VERSION 5.8 ;
BUSBITCHARS "[]" ;
DIVIDERCHAR "/" ;
UNITS
    DATABASE MICRONS 1000 ;
END UNITS

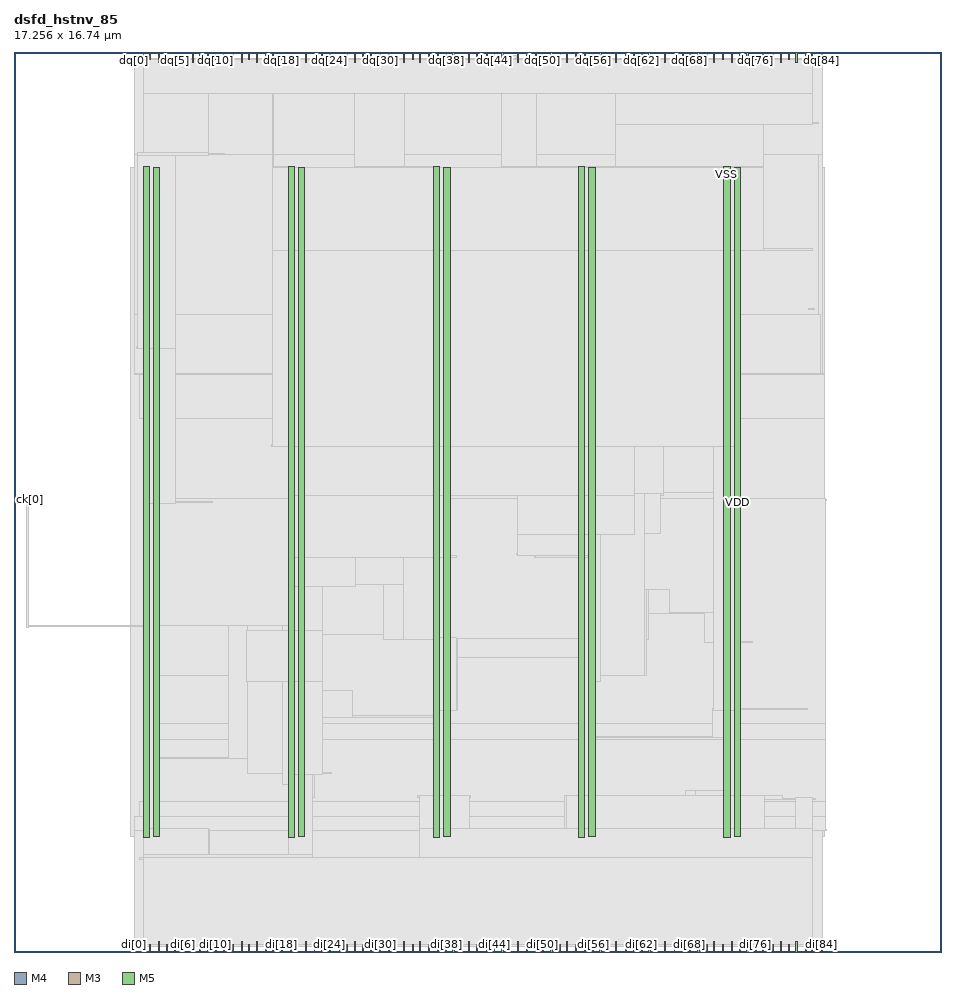
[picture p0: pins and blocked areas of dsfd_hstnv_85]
MACRO dsfd_hstnv_85
  FOREIGN dsfd_hstnv_85 0 0 ;
  CLASS BLOCK ;
  SIZE 17.256 BY 16.74 ;
  PIN ck[0]
    DIRECTION INPUT ;
    USE SIGNAL ;
    PORT
      LAYER M4 ;
        RECT  0 8.4 0.192 8.424 ;
    END
  END ck[0]
  PIN di[0]
    DIRECTION INPUT ;
    USE SIGNAL ;
    PORT
      LAYER M3 ;
        RECT  2.232 0 2.25 0.144 ;
    END
  END di[0]
  PIN di[10]
    DIRECTION INPUT ;
    USE SIGNAL ;
    PORT
      LAYER M3 ;
        RECT  3.744 0 3.762 0.144 ;
    END
  END di[10]
  PIN di[11]
    DIRECTION INPUT ;
    USE SIGNAL ;
    PORT
      LAYER M5 ;
        RECT  3.888 0 3.912 0.192 ;
    END
  END di[11]
  PIN di[12]
    DIRECTION INPUT ;
    USE SIGNAL ;
    PORT
      LAYER M3 ;
        RECT  4.068 0 4.086 0.144 ;
    END
  END di[12]
  PIN di[13]
    DIRECTION INPUT ;
    USE SIGNAL ;
    PORT
      LAYER M5 ;
        RECT  4.224 0 4.248 0.192 ;
    END
  END di[13]
  PIN di[14]
    DIRECTION INPUT ;
    USE SIGNAL ;
    PORT
      LAYER M3 ;
        RECT  4.356 0 4.374 0.144 ;
    END
  END di[14]
  PIN di[15]
    DIRECTION INPUT ;
    USE SIGNAL ;
    PORT
      LAYER M5 ;
        RECT  4.512 0 4.536 0.192 ;
    END
  END di[15]
  PIN di[16]
    DIRECTION INPUT ;
    USE SIGNAL ;
    PORT
      LAYER M3 ;
        RECT  4.68 0 4.698 0.144 ;
    END
  END di[16]
  PIN di[17]
    DIRECTION INPUT ;
    USE SIGNAL ;
    PORT
      LAYER M5 ;
        RECT  4.8 0 4.824 0.192 ;
    END
  END di[17]
  PIN di[18]
    DIRECTION INPUT ;
    USE SIGNAL ;
    PORT
      LAYER M3 ;
        RECT  4.968 0 4.986 0.144 ;
    END
  END di[18]
  PIN di[19]
    DIRECTION INPUT ;
    USE SIGNAL ;
    PORT
      LAYER M5 ;
        RECT  5.136 0 5.16 0.192 ;
    END
  END di[19]
  PIN di[1]
    DIRECTION INPUT ;
    USE SIGNAL ;
    PORT
      LAYER M5 ;
        RECT  2.4 0 2.424 0.192 ;
    END
  END di[1]
  PIN di[20]
    DIRECTION INPUT ;
    USE SIGNAL ;
    PORT
      LAYER M3 ;
        RECT  5.256 0 5.274 0.144 ;
    END
  END di[20]
  PIN di[21]
    DIRECTION INPUT ;
    USE SIGNAL ;
    PORT
      LAYER M5 ;
        RECT  5.424 0 5.448 0.192 ;
    END
  END di[21]
  PIN di[22]
    DIRECTION INPUT ;
    USE SIGNAL ;
    PORT
      LAYER M3 ;
        RECT  5.58 0 5.598 0.144 ;
    END
  END di[22]
  PIN di[23]
    DIRECTION INPUT ;
    USE SIGNAL ;
    PORT
      LAYER M5 ;
        RECT  5.712 0 5.736 0.192 ;
    END
  END di[23]
  PIN di[24]
    DIRECTION INPUT ;
    USE SIGNAL ;
    PORT
      LAYER M3 ;
        RECT  5.868 0 5.886 0.144 ;
    END
  END di[24]
  PIN di[25]
    DIRECTION INPUT ;
    USE SIGNAL ;
    PORT
      LAYER M5 ;
        RECT  6.048 0 6.072 0.192 ;
    END
  END di[25]
  PIN di[26]
    DIRECTION INPUT ;
    USE SIGNAL ;
    PORT
      LAYER M3 ;
        RECT  6.192 0 6.21 0.144 ;
    END
  END di[26]
  PIN di[27]
    DIRECTION INPUT ;
    USE SIGNAL ;
    PORT
      LAYER M5 ;
        RECT  6.336 0 6.36 0.192 ;
    END
  END di[27]
  PIN di[28]
    DIRECTION INPUT ;
    USE SIGNAL ;
    PORT
      LAYER M3 ;
        RECT  6.48 0 6.498 0.144 ;
    END
  END di[28]
  PIN di[29]
    DIRECTION INPUT ;
    USE SIGNAL ;
    PORT
      LAYER M5 ;
        RECT  6.624 0 6.648 0.192 ;
    END
  END di[29]
  PIN di[2]
    DIRECTION INPUT ;
    USE SIGNAL ;
    PORT
      LAYER M3 ;
        RECT  2.52 0 2.538 0.144 ;
    END
  END di[2]
  PIN di[30]
    DIRECTION INPUT ;
    USE SIGNAL ;
    PORT
      LAYER M3 ;
        RECT  6.804 0 6.822 0.144 ;
    END
  END di[30]
  PIN di[31]
    DIRECTION INPUT ;
    USE SIGNAL ;
    PORT
      LAYER M5 ;
        RECT  6.96 0 6.984 0.192 ;
    END
  END di[31]
  PIN di[32]
    DIRECTION INPUT ;
    USE SIGNAL ;
    PORT
      LAYER M3 ;
        RECT  7.092 0 7.11 0.144 ;
    END
  END di[32]
  PIN di[33]
    DIRECTION INPUT ;
    USE SIGNAL ;
    PORT
      LAYER M5 ;
        RECT  7.248 0 7.272 0.192 ;
    END
  END di[33]
  PIN di[34]
    DIRECTION INPUT ;
    USE SIGNAL ;
    PORT
      LAYER M3 ;
        RECT  7.416 0 7.434 0.144 ;
    END
  END di[34]
  PIN di[35]
    DIRECTION INPUT ;
    USE SIGNAL ;
    PORT
      LAYER M5 ;
        RECT  7.536 0 7.56 0.192 ;
    END
  END di[35]
  PIN di[36]
    DIRECTION INPUT ;
    USE SIGNAL ;
    PORT
      LAYER M3 ;
        RECT  7.704 0 7.722 0.144 ;
    END
  END di[36]
  PIN di[37]
    DIRECTION INPUT ;
    USE SIGNAL ;
    PORT
      LAYER M5 ;
        RECT  7.872 0 7.896 0.192 ;
    END
  END di[37]
  PIN di[38]
    DIRECTION INPUT ;
    USE SIGNAL ;
    PORT
      LAYER M3 ;
        RECT  8.028 0 8.046 0.144 ;
    END
  END di[38]
  PIN di[39]
    DIRECTION INPUT ;
    USE SIGNAL ;
    PORT
      LAYER M5 ;
        RECT  8.16 0 8.184 0.192 ;
    END
  END di[39]
  PIN di[3]
    DIRECTION INPUT ;
    USE SIGNAL ;
    PORT
      LAYER M5 ;
        RECT  2.688 0 2.712 0.192 ;
    END
  END di[3]
  PIN di[40]
    DIRECTION INPUT ;
    USE SIGNAL ;
    PORT
      LAYER M3 ;
        RECT  8.316 0 8.334 0.144 ;
    END
  END di[40]
  PIN di[41]
    DIRECTION INPUT ;
    USE SIGNAL ;
    PORT
      LAYER M5 ;
        RECT  8.448 0 8.472 0.192 ;
    END
  END di[41]
  PIN di[42]
    DIRECTION INPUT ;
    USE SIGNAL ;
    PORT
      LAYER M3 ;
        RECT  8.604 0 8.622 0.144 ;
    END
  END di[42]
  PIN di[43]
    DIRECTION INPUT ;
    USE SIGNAL ;
    PORT
      LAYER M5 ;
        RECT  8.784 0 8.808 0.192 ;
    END
  END di[43]
  PIN di[44]
    DIRECTION INPUT ;
    USE SIGNAL ;
    PORT
      LAYER M3 ;
        RECT  8.928 0 8.946 0.144 ;
    END
  END di[44]
  PIN di[45]
    DIRECTION INPUT ;
    USE SIGNAL ;
    PORT
      LAYER M5 ;
        RECT  9.072 0 9.096 0.192 ;
    END
  END di[45]
  PIN di[46]
    DIRECTION INPUT ;
    USE SIGNAL ;
    PORT
      LAYER M3 ;
        RECT  9.216 0 9.234 0.144 ;
    END
  END di[46]
  PIN di[47]
    DIRECTION INPUT ;
    USE SIGNAL ;
    PORT
      LAYER M5 ;
        RECT  9.36 0 9.384 0.192 ;
    END
  END di[47]
  PIN di[48]
    DIRECTION INPUT ;
    USE SIGNAL ;
    PORT
      LAYER M3 ;
        RECT  9.54 0 9.558 0.144 ;
    END
  END di[48]
  PIN di[49]
    DIRECTION INPUT ;
    USE SIGNAL ;
    PORT
      LAYER M5 ;
        RECT  9.696 0 9.72 0.192 ;
    END
  END di[49]
  PIN di[4]
    DIRECTION INPUT ;
    USE SIGNAL ;
    PORT
      LAYER M3 ;
        RECT  2.844 0 2.862 0.144 ;
    END
  END di[4]
  PIN di[50]
    DIRECTION INPUT ;
    USE SIGNAL ;
    PORT
      LAYER M3 ;
        RECT  9.828 0 9.846 0.144 ;
    END
  END di[50]
  PIN di[51]
    DIRECTION INPUT ;
    USE SIGNAL ;
    PORT
      LAYER M5 ;
        RECT  9.984 0 10.008 0.192 ;
    END
  END di[51]
  PIN di[52]
    DIRECTION INPUT ;
    USE SIGNAL ;
    PORT
      LAYER M3 ;
        RECT  10.152 0 10.17 0.144 ;
    END
  END di[52]
  PIN di[53]
    DIRECTION INPUT ;
    USE SIGNAL ;
    PORT
      LAYER M5 ;
        RECT  10.272 0 10.296 0.192 ;
    END
  END di[53]
  PIN di[54]
    DIRECTION INPUT ;
    USE SIGNAL ;
    PORT
      LAYER M3 ;
        RECT  10.44 0 10.458 0.144 ;
    END
  END di[54]
  PIN di[55]
    DIRECTION INPUT ;
    USE SIGNAL ;
    PORT
      LAYER M5 ;
        RECT  10.608 0 10.632 0.192 ;
    END
  END di[55]
  PIN di[56]
    DIRECTION INPUT ;
    USE SIGNAL ;
    PORT
      LAYER M3 ;
        RECT  10.764 0 10.782 0.144 ;
    END
  END di[56]
  PIN di[57]
    DIRECTION INPUT ;
    USE SIGNAL ;
    PORT
      LAYER M5 ;
        RECT  10.896 0 10.92 0.192 ;
    END
  END di[57]
  PIN di[58]
    DIRECTION INPUT ;
    USE SIGNAL ;
    PORT
      LAYER M3 ;
        RECT  11.052 0 11.07 0.144 ;
    END
  END di[58]
  PIN di[59]
    DIRECTION INPUT ;
    USE SIGNAL ;
    PORT
      LAYER M5 ;
        RECT  11.184 0 11.208 0.192 ;
    END
  END di[59]
  PIN di[5]
    DIRECTION INPUT ;
    USE SIGNAL ;
    PORT
      LAYER M5 ;
        RECT  2.976 0 3 0.192 ;
    END
  END di[5]
  PIN di[60]
    DIRECTION INPUT ;
    USE SIGNAL ;
    PORT
      LAYER M3 ;
        RECT  11.376 0 11.394 0.144 ;
    END
  END di[60]
  PIN di[61]
    DIRECTION INPUT ;
    USE SIGNAL ;
    PORT
      LAYER M5 ;
        RECT  11.52 0 11.544 0.192 ;
    END
  END di[61]
  PIN di[62]
    DIRECTION INPUT ;
    USE SIGNAL ;
    PORT
      LAYER M3 ;
        RECT  11.664 0 11.682 0.144 ;
    END
  END di[62]
  PIN di[63]
    DIRECTION INPUT ;
    USE SIGNAL ;
    PORT
      LAYER M5 ;
        RECT  11.808 0 11.832 0.192 ;
    END
  END di[63]
  PIN di[64]
    DIRECTION INPUT ;
    USE SIGNAL ;
    PORT
      LAYER M3 ;
        RECT  11.952 0 11.97 0.144 ;
    END
  END di[64]
  PIN di[65]
    DIRECTION INPUT ;
    USE SIGNAL ;
    PORT
      LAYER M5 ;
        RECT  12.096 0 12.12 0.192 ;
    END
  END di[65]
  PIN di[66]
    DIRECTION INPUT ;
    USE SIGNAL ;
    PORT
      LAYER M3 ;
        RECT  12.276 0 12.294 0.144 ;
    END
  END di[66]
  PIN di[67]
    DIRECTION INPUT ;
    USE SIGNAL ;
    PORT
      LAYER M5 ;
        RECT  12.432 0 12.456 0.192 ;
    END
  END di[67]
  PIN di[68]
    DIRECTION INPUT ;
    USE SIGNAL ;
    PORT
      LAYER M3 ;
        RECT  12.564 0 12.582 0.144 ;
    END
  END di[68]
  PIN di[69]
    DIRECTION INPUT ;
    USE SIGNAL ;
    PORT
      LAYER M5 ;
        RECT  12.72 0 12.744 0.192 ;
    END
  END di[69]
  PIN di[6]
    DIRECTION INPUT ;
    USE SIGNAL ;
    PORT
      LAYER M3 ;
        RECT  3.132 0 3.15 0.144 ;
    END
  END di[6]
  PIN di[70]
    DIRECTION INPUT ;
    USE SIGNAL ;
    PORT
      LAYER M3 ;
        RECT  12.888 0 12.906 0.144 ;
    END
  END di[70]
  PIN di[71]
    DIRECTION INPUT ;
    USE SIGNAL ;
    PORT
      LAYER M5 ;
        RECT  13.008 0 13.032 0.192 ;
    END
  END di[71]
  PIN di[72]
    DIRECTION INPUT ;
    USE SIGNAL ;
    PORT
      LAYER M3 ;
        RECT  13.176 0 13.194 0.144 ;
    END
  END di[72]
  PIN di[73]
    DIRECTION INPUT ;
    USE SIGNAL ;
    PORT
      LAYER M5 ;
        RECT  13.344 0 13.368 0.192 ;
    END
  END di[73]
  PIN di[74]
    DIRECTION INPUT ;
    USE SIGNAL ;
    PORT
      LAYER M3 ;
        RECT  13.5 0 13.518 0.144 ;
    END
  END di[74]
  PIN di[75]
    DIRECTION INPUT ;
    USE SIGNAL ;
    PORT
      LAYER M5 ;
        RECT  13.632 0 13.656 0.192 ;
    END
  END di[75]
  PIN di[76]
    DIRECTION INPUT ;
    USE SIGNAL ;
    PORT
      LAYER M3 ;
        RECT  13.788 0 13.806 0.144 ;
    END
  END di[76]
  PIN di[77]
    DIRECTION INPUT ;
    USE SIGNAL ;
    PORT
      LAYER M5 ;
        RECT  13.92 0 13.944 0.192 ;
    END
  END di[77]
  PIN di[78]
    DIRECTION INPUT ;
    USE SIGNAL ;
    PORT
      LAYER M3 ;
        RECT  14.112 0 14.13 0.144 ;
    END
  END di[78]
  PIN di[79]
    DIRECTION INPUT ;
    USE SIGNAL ;
    PORT
      LAYER M5 ;
        RECT  14.256 0 14.28 0.192 ;
    END
  END di[79]
  PIN di[7]
    DIRECTION INPUT ;
    USE SIGNAL ;
    PORT
      LAYER M5 ;
        RECT  3.312 0 3.336 0.192 ;
    END
  END di[7]
  PIN di[80]
    DIRECTION INPUT ;
    USE SIGNAL ;
    PORT
      LAYER M3 ;
        RECT  14.4 0 14.418 0.144 ;
    END
  END di[80]
  PIN di[81]
    DIRECTION INPUT ;
    USE SIGNAL ;
    PORT
      LAYER M5 ;
        RECT  14.544 0 14.568 0.192 ;
    END
  END di[81]
  PIN di[82]
    DIRECTION INPUT ;
    USE SIGNAL ;
    PORT
      LAYER M3 ;
        RECT  14.724 0 14.742 0.144 ;
    END
  END di[82]
  PIN di[83]
    DIRECTION INPUT ;
    USE SIGNAL ;
    PORT
      LAYER M5 ;
        RECT  14.832 0 14.856 0.192 ;
    END
  END di[83]
  PIN di[84]
    DIRECTION INPUT ;
    USE SIGNAL ;
    PORT
      LAYER M3 ;
        RECT  15.012 0 15.03 0.144 ;
    END
  END di[84]
  PIN di[8]
    DIRECTION INPUT ;
    USE SIGNAL ;
    PORT
      LAYER M3 ;
        RECT  3.456 0 3.474 0.144 ;
    END
  END di[8]
  PIN di[9]
    DIRECTION INPUT ;
    USE SIGNAL ;
    PORT
      LAYER M5 ;
        RECT  3.6 0 3.624 0.192 ;
    END
  END di[9]
  PIN dq[0]
    DIRECTION OUTPUT ;
    USE SIGNAL ;
    PORT
      LAYER M3 ;
        RECT  2.232 16.596 2.25 16.74 ;
    END
  END dq[0]
  PIN dq[10]
    DIRECTION OUTPUT ;
    USE SIGNAL ;
    PORT
      LAYER M3 ;
        RECT  3.744 16.596 3.762 16.74 ;
    END
  END dq[10]
  PIN dq[11]
    DIRECTION OUTPUT ;
    USE SIGNAL ;
    PORT
      LAYER M5 ;
        RECT  3.888 16.548 3.912 16.74 ;
    END
  END dq[11]
  PIN dq[12]
    DIRECTION OUTPUT ;
    USE SIGNAL ;
    PORT
      LAYER M3 ;
        RECT  4.068 16.596 4.086 16.74 ;
    END
  END dq[12]
  PIN dq[13]
    DIRECTION OUTPUT ;
    USE SIGNAL ;
    PORT
      LAYER M5 ;
        RECT  4.224 16.548 4.248 16.74 ;
    END
  END dq[13]
  PIN dq[14]
    DIRECTION OUTPUT ;
    USE SIGNAL ;
    PORT
      LAYER M3 ;
        RECT  4.356 16.596 4.374 16.74 ;
    END
  END dq[14]
  PIN dq[15]
    DIRECTION OUTPUT ;
    USE SIGNAL ;
    PORT
      LAYER M5 ;
        RECT  4.512 16.548 4.536 16.74 ;
    END
  END dq[15]
  PIN dq[16]
    DIRECTION OUTPUT ;
    USE SIGNAL ;
    PORT
      LAYER M3 ;
        RECT  4.68 16.596 4.698 16.74 ;
    END
  END dq[16]
  PIN dq[17]
    DIRECTION OUTPUT ;
    USE SIGNAL ;
    PORT
      LAYER M5 ;
        RECT  4.8 16.548 4.824 16.74 ;
    END
  END dq[17]
  PIN dq[18]
    DIRECTION OUTPUT ;
    USE SIGNAL ;
    PORT
      LAYER M3 ;
        RECT  4.968 16.596 4.986 16.74 ;
    END
  END dq[18]
  PIN dq[19]
    DIRECTION OUTPUT ;
    USE SIGNAL ;
    PORT
      LAYER M5 ;
        RECT  5.136 16.548 5.16 16.74 ;
    END
  END dq[19]
  PIN dq[1]
    DIRECTION OUTPUT ;
    USE SIGNAL ;
    PORT
      LAYER M5 ;
        RECT  2.4 16.548 2.424 16.74 ;
    END
  END dq[1]
  PIN dq[20]
    DIRECTION OUTPUT ;
    USE SIGNAL ;
    PORT
      LAYER M3 ;
        RECT  5.256 16.596 5.274 16.74 ;
    END
  END dq[20]
  PIN dq[21]
    DIRECTION OUTPUT ;
    USE SIGNAL ;
    PORT
      LAYER M5 ;
        RECT  5.424 16.548 5.448 16.74 ;
    END
  END dq[21]
  PIN dq[22]
    DIRECTION OUTPUT ;
    USE SIGNAL ;
    PORT
      LAYER M3 ;
        RECT  5.58 16.596 5.598 16.74 ;
    END
  END dq[22]
  PIN dq[23]
    DIRECTION OUTPUT ;
    USE SIGNAL ;
    PORT
      LAYER M5 ;
        RECT  5.712 16.548 5.736 16.74 ;
    END
  END dq[23]
  PIN dq[24]
    DIRECTION OUTPUT ;
    USE SIGNAL ;
    PORT
      LAYER M3 ;
        RECT  5.868 16.596 5.886 16.74 ;
    END
  END dq[24]
  PIN dq[25]
    DIRECTION OUTPUT ;
    USE SIGNAL ;
    PORT
      LAYER M5 ;
        RECT  6.048 16.548 6.072 16.74 ;
    END
  END dq[25]
  PIN dq[26]
    DIRECTION OUTPUT ;
    USE SIGNAL ;
    PORT
      LAYER M3 ;
        RECT  6.192 16.596 6.21 16.74 ;
    END
  END dq[26]
  PIN dq[27]
    DIRECTION OUTPUT ;
    USE SIGNAL ;
    PORT
      LAYER M5 ;
        RECT  6.336 16.548 6.36 16.74 ;
    END
  END dq[27]
  PIN dq[28]
    DIRECTION OUTPUT ;
    USE SIGNAL ;
    PORT
      LAYER M3 ;
        RECT  6.48 16.596 6.498 16.74 ;
    END
  END dq[28]
  PIN dq[29]
    DIRECTION OUTPUT ;
    USE SIGNAL ;
    PORT
      LAYER M5 ;
        RECT  6.624 16.548 6.648 16.74 ;
    END
  END dq[29]
  PIN dq[2]
    DIRECTION OUTPUT ;
    USE SIGNAL ;
    PORT
      LAYER M3 ;
        RECT  2.52 16.596 2.538 16.74 ;
    END
  END dq[2]
  PIN dq[30]
    DIRECTION OUTPUT ;
    USE SIGNAL ;
    PORT
      LAYER M3 ;
        RECT  6.804 16.596 6.822 16.74 ;
    END
  END dq[30]
  PIN dq[31]
    DIRECTION OUTPUT ;
    USE SIGNAL ;
    PORT
      LAYER M5 ;
        RECT  6.96 16.548 6.984 16.74 ;
    END
  END dq[31]
  PIN dq[32]
    DIRECTION OUTPUT ;
    USE SIGNAL ;
    PORT
      LAYER M3 ;
        RECT  7.092 16.596 7.11 16.74 ;
    END
  END dq[32]
  PIN dq[33]
    DIRECTION OUTPUT ;
    USE SIGNAL ;
    PORT
      LAYER M5 ;
        RECT  7.248 16.548 7.272 16.74 ;
    END
  END dq[33]
  PIN dq[34]
    DIRECTION OUTPUT ;
    USE SIGNAL ;
    PORT
      LAYER M3 ;
        RECT  7.416 16.596 7.434 16.74 ;
    END
  END dq[34]
  PIN dq[35]
    DIRECTION OUTPUT ;
    USE SIGNAL ;
    PORT
      LAYER M5 ;
        RECT  7.536 16.548 7.56 16.74 ;
    END
  END dq[35]
  PIN dq[36]
    DIRECTION OUTPUT ;
    USE SIGNAL ;
    PORT
      LAYER M3 ;
        RECT  7.704 16.596 7.722 16.74 ;
    END
  END dq[36]
  PIN dq[37]
    DIRECTION OUTPUT ;
    USE SIGNAL ;
    PORT
      LAYER M5 ;
        RECT  7.872 16.548 7.896 16.74 ;
    END
  END dq[37]
  PIN dq[38]
    DIRECTION OUTPUT ;
    USE SIGNAL ;
    PORT
      LAYER M3 ;
        RECT  8.028 16.596 8.046 16.74 ;
    END
  END dq[38]
  PIN dq[39]
    DIRECTION OUTPUT ;
    USE SIGNAL ;
    PORT
      LAYER M5 ;
        RECT  8.16 16.548 8.184 16.74 ;
    END
  END dq[39]
  PIN dq[3]
    DIRECTION OUTPUT ;
    USE SIGNAL ;
    PORT
      LAYER M5 ;
        RECT  2.688 16.548 2.712 16.74 ;
    END
  END dq[3]
  PIN dq[40]
    DIRECTION OUTPUT ;
    USE SIGNAL ;
    PORT
      LAYER M3 ;
        RECT  8.316 16.596 8.334 16.74 ;
    END
  END dq[40]
  PIN dq[41]
    DIRECTION OUTPUT ;
    USE SIGNAL ;
    PORT
      LAYER M5 ;
        RECT  8.448 16.548 8.472 16.74 ;
    END
  END dq[41]
  PIN dq[42]
    DIRECTION OUTPUT ;
    USE SIGNAL ;
    PORT
      LAYER M3 ;
        RECT  8.604 16.596 8.622 16.74 ;
    END
  END dq[42]
  PIN dq[43]
    DIRECTION OUTPUT ;
    USE SIGNAL ;
    PORT
      LAYER M5 ;
        RECT  8.784 16.548 8.808 16.74 ;
    END
  END dq[43]
  PIN dq[44]
    DIRECTION OUTPUT ;
    USE SIGNAL ;
    PORT
      LAYER M3 ;
        RECT  8.928 16.596 8.946 16.74 ;
    END
  END dq[44]
  PIN dq[45]
    DIRECTION OUTPUT ;
    USE SIGNAL ;
    PORT
      LAYER M5 ;
        RECT  9.072 16.548 9.096 16.74 ;
    END
  END dq[45]
  PIN dq[46]
    DIRECTION OUTPUT ;
    USE SIGNAL ;
    PORT
      LAYER M3 ;
        RECT  9.216 16.596 9.234 16.74 ;
    END
  END dq[46]
  PIN dq[47]
    DIRECTION OUTPUT ;
    USE SIGNAL ;
    PORT
      LAYER M5 ;
        RECT  9.36 16.548 9.384 16.74 ;
    END
  END dq[47]
  PIN dq[48]
    DIRECTION OUTPUT ;
    USE SIGNAL ;
    PORT
      LAYER M3 ;
        RECT  9.54 16.596 9.558 16.74 ;
    END
  END dq[48]
  PIN dq[49]
    DIRECTION OUTPUT ;
    USE SIGNAL ;
    PORT
      LAYER M5 ;
        RECT  9.696 16.548 9.72 16.74 ;
    END
  END dq[49]
  PIN dq[4]
    DIRECTION OUTPUT ;
    USE SIGNAL ;
    PORT
      LAYER M3 ;
        RECT  2.844 16.596 2.862 16.74 ;
    END
  END dq[4]
  PIN dq[50]
    DIRECTION OUTPUT ;
    USE SIGNAL ;
    PORT
      LAYER M3 ;
        RECT  9.828 16.596 9.846 16.74 ;
    END
  END dq[50]
  PIN dq[51]
    DIRECTION OUTPUT ;
    USE SIGNAL ;
    PORT
      LAYER M5 ;
        RECT  9.984 16.548 10.008 16.74 ;
    END
  END dq[51]
  PIN dq[52]
    DIRECTION OUTPUT ;
    USE SIGNAL ;
    PORT
      LAYER M3 ;
        RECT  10.152 16.596 10.17 16.74 ;
    END
  END dq[52]
  PIN dq[53]
    DIRECTION OUTPUT ;
    USE SIGNAL ;
    PORT
      LAYER M5 ;
        RECT  10.272 16.548 10.296 16.74 ;
    END
  END dq[53]
  PIN dq[54]
    DIRECTION OUTPUT ;
    USE SIGNAL ;
    PORT
      LAYER M3 ;
        RECT  10.44 16.596 10.458 16.74 ;
    END
  END dq[54]
  PIN dq[55]
    DIRECTION OUTPUT ;
    USE SIGNAL ;
    PORT
      LAYER M5 ;
        RECT  10.608 16.548 10.632 16.74 ;
    END
  END dq[55]
  PIN dq[56]
    DIRECTION OUTPUT ;
    USE SIGNAL ;
    PORT
      LAYER M3 ;
        RECT  10.764 16.596 10.782 16.74 ;
    END
  END dq[56]
  PIN dq[57]
    DIRECTION OUTPUT ;
    USE SIGNAL ;
    PORT
      LAYER M5 ;
        RECT  10.896 16.548 10.92 16.74 ;
    END
  END dq[57]
  PIN dq[58]
    DIRECTION OUTPUT ;
    USE SIGNAL ;
    PORT
      LAYER M3 ;
        RECT  11.052 16.596 11.07 16.74 ;
    END
  END dq[58]
  PIN dq[59]
    DIRECTION OUTPUT ;
    USE SIGNAL ;
    PORT
      LAYER M5 ;
        RECT  11.184 16.548 11.208 16.74 ;
    END
  END dq[59]
  PIN dq[5]
    DIRECTION OUTPUT ;
    USE SIGNAL ;
    PORT
      LAYER M5 ;
        RECT  2.976 16.548 3 16.74 ;
    END
  END dq[5]
  PIN dq[60]
    DIRECTION OUTPUT ;
    USE SIGNAL ;
    PORT
      LAYER M3 ;
        RECT  11.376 16.596 11.394 16.74 ;
    END
  END dq[60]
  PIN dq[61]
    DIRECTION OUTPUT ;
    USE SIGNAL ;
    PORT
      LAYER M5 ;
        RECT  11.52 16.548 11.544 16.74 ;
    END
  END dq[61]
  PIN dq[62]
    DIRECTION OUTPUT ;
    USE SIGNAL ;
    PORT
      LAYER M3 ;
        RECT  11.664 16.596 11.682 16.74 ;
    END
  END dq[62]
  PIN dq[63]
    DIRECTION OUTPUT ;
    USE SIGNAL ;
    PORT
      LAYER M5 ;
        RECT  11.808 16.548 11.832 16.74 ;
    END
  END dq[63]
  PIN dq[64]
    DIRECTION OUTPUT ;
    USE SIGNAL ;
    PORT
      LAYER M3 ;
        RECT  11.952 16.596 11.97 16.74 ;
    END
  END dq[64]
  PIN dq[65]
    DIRECTION OUTPUT ;
    USE SIGNAL ;
    PORT
      LAYER M5 ;
        RECT  12.096 16.548 12.12 16.74 ;
    END
  END dq[65]
  PIN dq[66]
    DIRECTION OUTPUT ;
    USE SIGNAL ;
    PORT
      LAYER M3 ;
        RECT  12.276 16.596 12.294 16.74 ;
    END
  END dq[66]
  PIN dq[67]
    DIRECTION OUTPUT ;
    USE SIGNAL ;
    PORT
      LAYER M5 ;
        RECT  12.432 16.548 12.456 16.74 ;
    END
  END dq[67]
  PIN dq[68]
    DIRECTION OUTPUT ;
    USE SIGNAL ;
    PORT
      LAYER M3 ;
        RECT  12.564 16.596 12.582 16.74 ;
    END
  END dq[68]
  PIN dq[69]
    DIRECTION OUTPUT ;
    USE SIGNAL ;
    PORT
      LAYER M5 ;
        RECT  12.72 16.548 12.744 16.74 ;
    END
  END dq[69]
  PIN dq[6]
    DIRECTION OUTPUT ;
    USE SIGNAL ;
    PORT
      LAYER M3 ;
        RECT  3.132 16.596 3.15 16.74 ;
    END
  END dq[6]
  PIN dq[70]
    DIRECTION OUTPUT ;
    USE SIGNAL ;
    PORT
      LAYER M3 ;
        RECT  12.888 16.596 12.906 16.74 ;
    END
  END dq[70]
  PIN dq[71]
    DIRECTION OUTPUT ;
    USE SIGNAL ;
    PORT
      LAYER M5 ;
        RECT  13.008 16.548 13.032 16.74 ;
    END
  END dq[71]
  PIN dq[72]
    DIRECTION OUTPUT ;
    USE SIGNAL ;
    PORT
      LAYER M3 ;
        RECT  13.176 16.596 13.194 16.74 ;
    END
  END dq[72]
  PIN dq[73]
    DIRECTION OUTPUT ;
    USE SIGNAL ;
    PORT
      LAYER M5 ;
        RECT  13.344 16.548 13.368 16.74 ;
    END
  END dq[73]
  PIN dq[74]
    DIRECTION OUTPUT ;
    USE SIGNAL ;
    PORT
      LAYER M3 ;
        RECT  13.5 16.596 13.518 16.74 ;
    END
  END dq[74]
  PIN dq[75]
    DIRECTION OUTPUT ;
    USE SIGNAL ;
    PORT
      LAYER M5 ;
        RECT  13.632 16.548 13.656 16.74 ;
    END
  END dq[75]
  PIN dq[76]
    DIRECTION OUTPUT ;
    USE SIGNAL ;
    PORT
      LAYER M3 ;
        RECT  13.788 16.596 13.806 16.74 ;
    END
  END dq[76]
  PIN dq[77]
    DIRECTION OUTPUT ;
    USE SIGNAL ;
    PORT
      LAYER M5 ;
        RECT  13.92 16.548 13.944 16.74 ;
    END
  END dq[77]
  PIN dq[78]
    DIRECTION OUTPUT ;
    USE SIGNAL ;
    PORT
      LAYER M3 ;
        RECT  14.112 16.596 14.13 16.74 ;
    END
  END dq[78]
  PIN dq[79]
    DIRECTION OUTPUT ;
    USE SIGNAL ;
    PORT
      LAYER M5 ;
        RECT  14.256 16.548 14.28 16.74 ;
    END
  END dq[79]
  PIN dq[7]
    DIRECTION OUTPUT ;
    USE SIGNAL ;
    PORT
      LAYER M5 ;
        RECT  3.312 16.548 3.336 16.74 ;
    END
  END dq[7]
  PIN dq[80]
    DIRECTION OUTPUT ;
    USE SIGNAL ;
    PORT
      LAYER M3 ;
        RECT  14.4 16.596 14.418 16.74 ;
    END
  END dq[80]
  PIN dq[81]
    DIRECTION OUTPUT ;
    USE SIGNAL ;
    PORT
      LAYER M5 ;
        RECT  14.544 16.548 14.568 16.74 ;
    END
  END dq[81]
  PIN dq[82]
    DIRECTION OUTPUT ;
    USE SIGNAL ;
    PORT
      LAYER M3 ;
        RECT  14.724 16.596 14.742 16.74 ;
    END
  END dq[82]
  PIN dq[83]
    DIRECTION OUTPUT ;
    USE SIGNAL ;
    PORT
      LAYER M5 ;
        RECT  14.832 16.548 14.856 16.74 ;
    END
  END dq[83]
  PIN dq[84]
    DIRECTION OUTPUT ;
    USE SIGNAL ;
    PORT
      LAYER M3 ;
        RECT  15.012 16.596 15.03 16.74 ;
    END
  END dq[84]
  PIN dq[8]
    DIRECTION OUTPUT ;
    USE SIGNAL ;
    PORT
      LAYER M3 ;
        RECT  3.456 16.596 3.474 16.74 ;
    END
  END dq[8]
  PIN dq[9]
    DIRECTION OUTPUT ;
    USE SIGNAL ;
    PORT
      LAYER M5 ;
        RECT  3.6 16.548 3.624 16.74 ;
    END
  END dq[9]
  PIN VDD
    DIRECTION INOUT ;
    USE POWER ;
    PORT
      LAYER M5 ;
        RECT  13.392 2.151 13.512 14.589 ;
        RECT  10.692 2.151 10.812 14.589 ;
        RECT  7.992 2.151 8.112 14.589 ;
        RECT  5.292 2.151 5.412 14.589 ;
        RECT  2.592 2.151 2.712 14.589 ;
    END
  END VDD
  PIN VSS
    DIRECTION INOUT ;
    USE GROUND ;
    PORT
      LAYER M5 ;
        RECT  13.2 2.137 13.32 14.603 ;
        RECT  10.5 2.137 10.62 14.603 ;
        RECT  7.8 2.137 7.92 14.603 ;
        RECT  5.1 2.137 5.22 14.603 ;
        RECT  2.4 2.137 2.52 14.603 ;
    END
  END VSS
  OBS
    LAYER RVTN ;
     RECT  2.16 2.16 15.066 2.295 ;
     RECT  2.16 2.565 15.066 2.835 ;
     RECT  2.16 3.105 15.066 3.375 ;
     RECT  2.16 3.645 15.066 3.915 ;
     RECT  2.16 4.185 15.066 4.455 ;
     RECT  2.16 4.725 15.066 4.995 ;
     RECT  2.16 5.265 15.066 5.535 ;
     RECT  2.16 5.805 15.066 6.075 ;
     RECT  2.16 6.345 15.066 6.615 ;
     RECT  2.16 6.885 15.066 7.155 ;
     RECT  2.16 7.425 15.066 7.695 ;
     RECT  2.16 7.965 15.066 8.235 ;
     RECT  2.16 8.505 15.066 8.775 ;
     RECT  2.16 9.045 15.066 9.315 ;
     RECT  2.16 9.585 15.066 9.855 ;
     RECT  2.16 10.125 15.066 10.395 ;
     RECT  2.16 10.665 15.066 10.935 ;
     RECT  2.16 11.205 15.066 11.475 ;
     RECT  2.16 11.745 15.066 12.015 ;
     RECT  2.16 12.285 15.066 12.555 ;
     RECT  2.16 12.825 15.066 13.095 ;
     RECT  2.16 13.365 15.066 13.635 ;
     RECT  2.16 13.905 15.066 14.175 ;
     RECT  2.16 14.445 15.066 14.58 ;
    LAYER RVTP ;
     RECT  2.16 2.295 15.066 2.565 ;
     RECT  2.16 2.835 15.066 3.105 ;
     RECT  2.16 3.375 15.066 3.645 ;
     RECT  2.16 3.915 15.066 4.185 ;
     RECT  2.16 4.455 15.066 4.725 ;
     RECT  2.16 4.995 15.066 5.265 ;
     RECT  2.16 5.535 15.066 5.805 ;
     RECT  2.16 6.075 15.066 6.345 ;
     RECT  2.16 6.615 15.066 6.885 ;
     RECT  2.16 7.155 15.066 7.425 ;
     RECT  2.16 7.695 15.066 7.965 ;
     RECT  2.16 8.235 15.066 8.505 ;
     RECT  2.16 8.775 15.066 9.045 ;
     RECT  2.16 9.315 15.066 9.585 ;
     RECT  2.16 9.855 15.066 10.125 ;
     RECT  2.16 10.395 15.066 10.665 ;
     RECT  2.16 10.935 15.066 11.205 ;
     RECT  2.16 11.475 15.066 11.745 ;
     RECT  2.16 12.015 15.066 12.285 ;
     RECT  2.16 12.555 15.066 12.825 ;
     RECT  2.16 13.095 15.066 13.365 ;
     RECT  2.16 13.635 15.066 13.905 ;
     RECT  2.16 14.175 15.066 14.445 ;
    LAYER M1 ;
     RECT  2.16 2.151 15.066 14.589 ;
    LAYER M2 ;
     RECT  2.16 2.151 2.515 14.589 ;
     RECT  2.515 0.144 2.759 0.162 ;
     RECT  2.515 2.151 3.451 14.859 ;
     RECT  4.351 0.144 4.451 0.162 ;
     RECT  3.451 2.151 4.559 14.904 ;
     RECT  5.251 0.144 5.459 0.162 ;
     RECT  5.251 15.966 5.575 15.984 ;
     RECT  5.575 15.966 5.863 16.056 ;
     RECT  5.863 15.966 6.251 16.092 ;
     RECT  4.559 2.151 6.475 14.589 ;
     RECT  6.251 15.966 6.647 16.056 ;
     RECT  6.647 15.966 6.863 15.984 ;
     RECT  6.475 2.151 7.187 14.859 ;
     RECT  7.187 2.151 8.023 14.814 ;
     RECT  8.023 0.144 8.159 0.162 ;
     RECT  8.023 2.151 8.987 14.859 ;
     RECT  8.311 15.966 9.211 15.984 ;
     RECT  9.211 15.966 9.247 16.596 ;
     RECT  9.247 15.966 9.347 16.668 ;
     RECT  9.347 15.966 9.599 15.984 ;
     RECT  8.987 2.151 9.823 14.589 ;
     RECT  10.471 0.144 10.787 0.162 ;
     RECT  9.823 2.151 10.787 14.859 ;
     RECT  10.435 15.966 11.147 15.984 ;
     RECT  10.787 2.151 11.659 14.589 ;
     RECT  11.947 15.966 12.263 15.984 ;
     RECT  12.271 0.144 12.659 0.162 ;
     RECT  11.659 2.151 13.783 14.859 ;
     RECT  13.783 1.728 14.207 14.859 ;
     RECT  14.207 2.151 15.035 14.859 ;
     RECT  15.035 2.151 15.066 14.589 ;
     RECT  15.066 8.406 15.071 9.108 ;
     RECT  15.066 10.746 15.071 10.764 ;
     RECT  15.066 2.268 15.107 2.286 ;
     RECT  15.071 8.406 15.107 8.424 ;
    LAYER M3 ;
     RECT  2.232 0.108 15.03 2.263 ;
     RECT  2.232 2.263 15.102 2.525 ;
     RECT  2.34 2.525 15.102 2.795 ;
     RECT  2.415 2.795 15.102 3.955 ;
     RECT  2.412 3.955 15.102 4.253 ;
     RECT  2.415 4.253 15.102 8.429 ;
     RECT  2.415 8.429 15.066 9.931 ;
     RECT  2.34 9.931 15.066 10.741 ;
     RECT  2.232 10.741 15.066 10.769 ;
     RECT  2.232 10.769 14.994 11.849 ;
     RECT  2.232 11.849 14.958 14.836 ;
     RECT  2.232 14.836 15.03 16.62 ;
     RECT  9.252 16.62 9.342 16.673 ;
    LAYER M4 ;
     RECT  0.156 8.4 0.275 8.424 ;
     RECT  2.329 1.728 2.408 1.752 ;
     RECT  0.229 6.048 2.408 6.072 ;
     RECT  2.285 11.232 2.408 11.256 ;
     RECT  2.293 14.832 2.408 14.856 ;
     RECT  2.408 1.728 2.435 14.856 ;
     RECT  2.435 1.728 2.512 14.592 ;
     RECT  2.512 1.728 2.704 14.322 ;
     RECT  2.704 1.728 3.635 2.28 ;
     RECT  2.704 8.352 3.701 8.376 ;
     RECT  3.589 14.832 3.917 14.856 ;
     RECT  2.704 3.6 3.985 3.624 ;
     RECT  2.704 5.136 3.985 6.072 ;
     RECT  3.985 3.6 4.345 6.072 ;
     RECT  2.677 15.984 4.492 16.008 ;
     RECT  3.635 1.728 4.853 1.8 ;
     RECT  4.345 3.312 4.993 6.072 ;
     RECT  4.993 3.12 5.108 6.072 ;
     RECT  4.789 9.408 5.108 9.432 ;
     RECT  5.108 2.016 5.212 14.592 ;
     RECT  5.212 2.016 5.404 14.322 ;
     RECT  5.404 2.88 5.581 3.336 ;
     RECT  4.492 15.984 5.645 16.056 ;
     RECT  5.404 4.368 5.747 6.84 ;
     RECT  5.413 0.192 5.753 0.216 ;
     RECT  5.581 3.312 5.897 3.336 ;
     RECT  5.747 4.368 6.293 4.872 ;
     RECT  5.747 5.904 6.865 6.84 ;
     RECT  6.865 5.808 7.237 6.84 ;
     RECT  6.037 1.728 7.808 1.752 ;
     RECT  7.513 2.88 7.808 2.904 ;
     RECT  6.293 4.368 7.808 4.392 ;
     RECT  7.237 5.808 7.808 7.368 ;
     RECT  6.613 11.376 7.808 11.4 ;
     RECT  7.669 0.192 7.907 0.216 ;
     RECT  7.808 1.728 7.912 14.592 ;
     RECT  7.912 1.728 8.104 14.322 ;
     RECT  5.645 15.984 8.149 16.008 ;
     RECT  8.104 7.344 8.237 7.368 ;
     RECT  8.104 4.512 8.243 5.832 ;
     RECT  8.149 15.984 8.437 16.056 ;
     RECT  8.104 2.88 8.489 2.904 ;
     RECT  8.437 15.984 8.921 16.104 ;
     RECT  8.921 16.08 9.029 16.104 ;
     RECT  8.104 1.728 9.137 1.752 ;
     RECT  9.349 7.392 9.685 7.416 ;
     RECT  9.644 0.528 9.731 0.552 ;
     RECT  9.308 2.256 10.241 2.28 ;
     RECT  10.241 2.256 10.508 2.904 ;
     RECT  8.243 5.472 10.508 5.832 ;
     RECT  9.685 7.344 10.508 7.416 ;
     RECT  8.104 8.496 10.508 8.52 ;
     RECT  10.508 2.148 10.597 14.592 ;
     RECT  9.932 15.984 10.597 16.008 ;
     RECT  10.597 1.728 10.612 14.592 ;
     RECT  10.612 1.728 10.804 14.322 ;
     RECT  10.597 15.984 10.885 16.056 ;
     RECT  10.804 5.04 10.901 8.52 ;
     RECT  10.885 15.984 11.045 16.104 ;
     RECT  11.045 15.984 11.225 16.056 ;
     RECT  10.901 5.136 11.729 8.52 ;
     RECT  11.729 5.136 11.765 6.744 ;
     RECT  11.765 5.808 11.801 6.744 ;
     RECT  11.797 14.784 11.981 14.808 ;
     RECT  11.729 7.776 12.017 8.52 ;
     RECT  12.017 8.496 12.085 8.52 ;
     RECT  12.085 8.496 12.089 9.432 ;
     RECT  11.801 6.288 12.197 6.744 ;
     RECT  10.804 1.728 12.305 1.752 ;
     RECT  11.225 16.032 12.421 16.056 ;
     RECT  10.804 2.88 12.481 2.904 ;
     RECT  12.481 2.88 12.668 3 ;
     RECT  12.197 6.288 12.841 6.312 ;
     RECT  12.421 15.984 12.881 16.056 ;
     RECT  10.804 3.984 12.997 4.008 ;
     RECT  12.668 2.148 13.208 3 ;
     RECT  12.997 3.984 13.208 4.536 ;
     RECT  12.841 5.76 13.208 6.312 ;
     RECT  12.089 8.544 13.208 9.432 ;
     RECT  13.208 2.148 13.333 14.592 ;
     RECT  13.333 1.728 13.504 14.592 ;
     RECT  13.589 14.784 13.673 14.808 ;
     RECT  13.504 5.76 13.745 5.784 ;
     RECT  13.504 1.728 13.955 2.904 ;
     RECT  13.955 2.832 14.285 2.904 ;
     RECT  12.881 15.984 14.291 16.008 ;
     RECT  13.955 1.728 14.321 1.752 ;
     RECT  13.504 4.512 14.753 4.536 ;
     RECT  13.504 13.056 14.861 13.08 ;
     RECT  14.785 11.952 14.897 11.976 ;
     RECT  14.285 2.832 14.905 2.856 ;
     RECT  14.533 15.408 14.969 15.432 ;
    LAYER M5 ;
     RECT  2.4 0.144 14.856 1.763 ;
     RECT  2.4 1.763 5.544 1.811 ;
     RECT  2.4 1.811 3.624 2.291 ;
     RECT  7.536 1.763 14.856 2.291 ;
     RECT  14.544 2.291 14.856 2.867 ;
     RECT  7.536 2.291 8.472 2.915 ;
     RECT  10.272 2.291 13.512 2.915 ;
     RECT  5.1 1.811 5.544 3.301 ;
     RECT  7.8 2.915 8.112 4.501 ;
     RECT  13.2 2.915 13.512 4.501 ;
     RECT  5.1 3.301 5.736 5.029 ;
     RECT  7.8 4.501 8.232 5.843 ;
     RECT  4.32 5.029 5.736 5.987 ;
     RECT  5.1 5.987 5.736 6.805 ;
     RECT  5.1 6.805 6.36 7.333 ;
     RECT  7.8 5.843 8.112 7.333 ;
     RECT  10.5 2.915 10.812 7.333 ;
     RECT  9.696 7.333 10.812 7.381 ;
     RECT  9.36 7.381 10.812 7.765 ;
     RECT  2.4 2.291 2.712 8.341 ;
     RECT  0.24 6.037 0.264 8.435 ;
     RECT  5.1 7.333 8.112 8.485 ;
     RECT  9.36 7.765 11.544 8.485 ;
     RECT  5.1 8.485 11.544 9.397 ;
     RECT  13.008 4.501 13.512 9.397 ;
     RECT  2.4 8.341 3 11.221 ;
     RECT  4.8 9.397 13.512 13.045 ;
     RECT  4.8 13.045 13.944 14.589 ;
     RECT  4.8 14.589 5.22 14.603 ;
     RECT  6.336 14.589 7.92 14.603 ;
     RECT  9.072 14.589 13.944 14.603 ;
     RECT  2.304 11.221 3 14.821 ;
     RECT  2.304 14.821 3.624 14.867 ;
     RECT  11.184 14.603 13.944 15.397 ;
     RECT  2.4 14.867 3.624 15.973 ;
     RECT  4.8 14.603 4.824 15.973 ;
     RECT  6.336 14.603 7.272 15.973 ;
     RECT  9.072 14.603 9.72 15.973 ;
     RECT  11.184 15.397 14.856 15.973 ;
     RECT  2.4 15.973 14.856 16.592 ;
  END
END dsfd_hstnv_85
END LIBRARY
